One B-rep face of a CAD part: STEP entity #1192.
In plain terms, the planar face has unit normal (0, 1, 0).
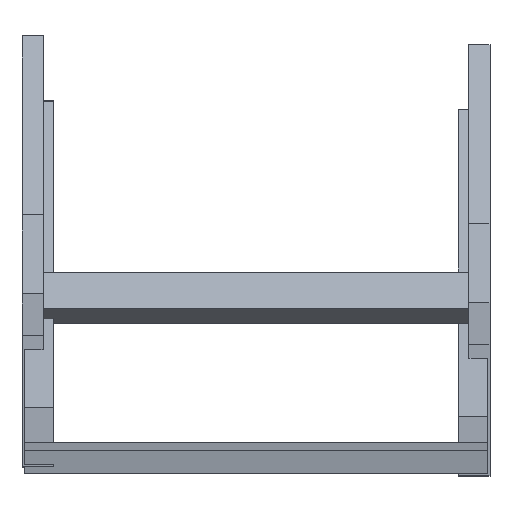
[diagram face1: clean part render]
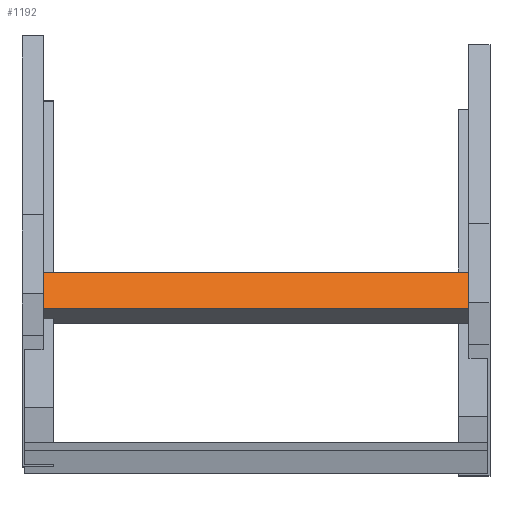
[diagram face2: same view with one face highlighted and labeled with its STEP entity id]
Its self-contained STEP definition (entity closure, numbers rounded to 3 decimals):
#31 = VERTEX_POINT ( 'NONE', #1065 ) ;
#94 = EDGE_CURVE ( 'NONE', #496, #518, #427, .T. ) ;
#182 = CARTESIAN_POINT ( 'NONE',  ( 198., 20., 20.25 ) ) ;
#286 = CARTESIAN_POINT ( 'NONE',  ( 198., 20., 20.25 ) ) ;
#327 = EDGE_CURVE ( 'NONE', #1596, #518, #1522, .T. ) ;
#333 = DIRECTION ( 'NONE',  ( 0., 0., 1. ) ) ;
#346 = ORIENTED_EDGE ( 'NONE', *, *, #1600, .T. ) ;
#362 = ORIENTED_EDGE ( 'NONE', *, *, #327, .T. ) ;
#422 = CARTESIAN_POINT ( 'NONE',  ( 198., 20., -20.25 ) ) ;
#427 = LINE ( 'NONE', #286, #1676 ) ;
#438 = EDGE_CURVE ( 'NONE', #31, #496, #836, .T. ) ;
#489 = CARTESIAN_POINT ( 'NONE',  ( -198., 20., 20.25 ) ) ;
#496 = VERTEX_POINT ( 'NONE', #1667 ) ;
#514 = ORIENTED_EDGE ( 'NONE', *, *, #438, .F. ) ;
#518 = VERTEX_POINT ( 'NONE', #1542 ) ;
#612 = VECTOR ( 'NONE', #333, 1000. ) ;
#640 = PLANE ( 'NONE',  #1313 ) ;
#716 = VECTOR ( 'NONE', #1003, 1000. ) ;
#829 = DIRECTION ( 'NONE',  ( -1., 0., 0. ) ) ;
#836 = LINE ( 'NONE', #182, #612 ) ;
#915 = EDGE_LOOP ( 'NONE', ( #362, #1140, #514, #346 ) ) ;
#1003 = DIRECTION ( 'NONE',  ( 0., 0., 1. ) ) ;
#1061 = DIRECTION ( 'NONE',  ( -1., 0., 0. ) ) ;
#1065 = CARTESIAN_POINT ( 'NONE',  ( 198., 20., -20.25 ) ) ;
#1140 = ORIENTED_EDGE ( 'NONE', *, *, #94, .F. ) ;
#1168 = LINE ( 'NONE', #422, #1623 ) ;
#1192 = ADVANCED_FACE ( 'NONE', ( #1557 ), #640, .F. ) ;
#1261 = DIRECTION ( 'NONE',  ( 0., 0., -1. ) ) ;
#1270 = DIRECTION ( 'NONE',  ( 0., -1., 0. ) ) ;
#1313 = AXIS2_PLACEMENT_3D ( 'NONE', #1520, #1270, #1261 ) ;
#1520 = CARTESIAN_POINT ( 'NONE',  ( 198., 20., 20.25 ) ) ;
#1522 = LINE ( 'NONE', #489, #716 ) ;
#1542 = CARTESIAN_POINT ( 'NONE',  ( -198., 20., 20.25 ) ) ;
#1557 = FACE_OUTER_BOUND ( 'NONE', #915, .T. ) ;
#1596 = VERTEX_POINT ( 'NONE', #1664 ) ;
#1600 = EDGE_CURVE ( 'NONE', #31, #1596, #1168, .T. ) ;
#1623 = VECTOR ( 'NONE', #1061, 1000. ) ;
#1664 = CARTESIAN_POINT ( 'NONE',  ( -198., 20., -20.25 ) ) ;
#1667 = CARTESIAN_POINT ( 'NONE',  ( 198., 20., 20.25 ) ) ;
#1676 = VECTOR ( 'NONE', #829, 1000. ) ;
